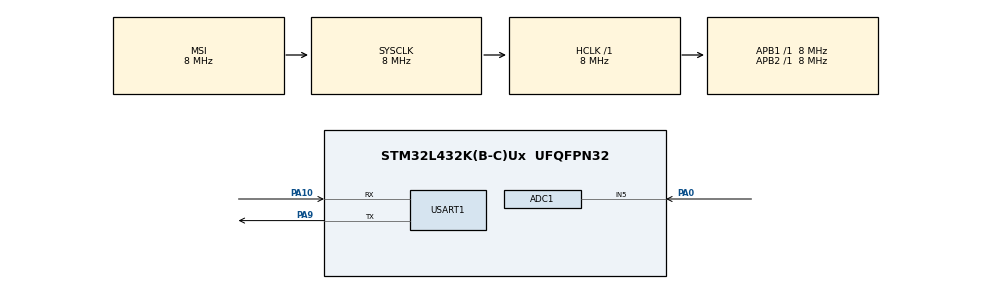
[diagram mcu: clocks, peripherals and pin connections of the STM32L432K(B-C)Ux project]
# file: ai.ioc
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ADC1.Channel-0\#ChannelRegularConversion=ADC_CHANNEL_5
ADC1.ContinuousConvMode=ENABLE
ADC1.NbrOfConversionFlag=1
ADC1.OffsetNumber-0\#ChannelRegularConversion=ADC_OFFSET_NONE
ADC1.Rank-0\#ChannelRegularConversion=1
ADC1.SamplingTime-0\#ChannelRegularConversion=ADC_SAMPLETIME_2CYCLES_5
ADC1.master=1
Mcu.Family=STM32L4
Mcu.Name=STM32L432K(B-C)Ux
Mcu.Package=UFQFPN32
NVIC.PriorityGroup=NVIC_PRIORITYGROUP_4
PA0.Signal=ADCx_IN5
PA10.Mode=Asynchronous
PA10.Signal=USART1_RX
PA9.Mode=Asynchronous
PA9.Signal=USART1_TX
ProjectManager.HeapSize=0x2000
ProjectManager.StackSize=0x4000
ProjectManager.TargetToolchain=MDK-ARM V5.27
RCC.ADCFreq_Value=32000000
RCC.AHBFreq_Value=8000000
RCC.APB1Freq_Value=8000000
RCC.APB1TimFreq_Value=8000000
RCC.APB2Freq_Value=8000000
RCC.APB2TimFreq_Value=8000000
RCC.CortexFreq_Value=8000000
RCC.HCLKFreq_Value=8000000
RCC.HSE_VALUE=8000000
RCC.HSI48_VALUE=48000000
RCC.HSI_VALUE=16000000
RCC.LSE_VALUE=32768
RCC.MSIClockRange=RCC_MSIRANGE_7
RCC.MSI_VALUE=8000000
RCC.SYSCLKFreq_VALUE=8000000
RCC.USBFreq_Value=32000000
RCC.VCOOutputFreq_Value=64000000
SH.ADCx_IN5.0=ADC1_IN5,IN5-Single-Ended
STMicroelectronics.X-CUBE-AI.5.0.0.ActivationBufferSizeList=400
STMicroelectronics.X-CUBE-AI.5.0.0.ApplicationCcArtificialOoIntelligenceJjApplication=ApplicationTemplate
STMicroelectronics.X-CUBE-AI.5.0.0.HeapSize=0x2000
STMicroelectronics.X-CUBE-AI.5.0.0.InternalRamActivationBufferMaxSize=AI_ECG_NETWORK_DATA_ACTIVATIONS_SIZE
STMicroelectronics.X-CUBE-AI.5.0.0.LatestDirectoryUsed-d3a59a0a51c23c8c7a7c3687464f654e9c9f9513bd5a042f653194bf225a79ad=C\:\\Users\\shalan\\Desktop\\Embedded\\Proj2
STMicroelectronics.X-CUBE-AI.5.0.0.MaximumNumberOfInputLayer=1
STMicroelectronics.X-CUBE-AI.5.0.0.MaximumNumberOfOutputLayer=1
STMicroelectronics.X-CUBE-AI.5.0.0.MaximumSizeOfInputLayer=748
STMicroelectronics.X-CUBE-AI.5.0.0.MaximumSizeOfOutputLayer=20
STMicroelectronics.X-CUBE-AI.5.0.0.ModelActualCompression-d3a59a0a51c23c8c7a7c3687464f654e9c9f9513bd5a042f653194bf225a79ad=0.0
STMicroelectronics.X-CUBE-AI.5.0.0.ModelCompression-d3a59a0a51c23c8c7a7c3687464f654e9c9f9513bd5a042f653194bf225a79ad=4
STMicroelectronics.X-CUBE-AI.5.0.0.ModelFlashOccupation-d3a59a0a51c23c8c7a7c3687464f654e9c9f9513bd5a042f653194bf225a79ad=15320
STMicroelectronics.X-CUBE-AI.5.0.0.ModelHashList=d3a59a0a51c23c8c7a7c3687464f654e9c9f9513bd5a042f653194bf225a79ad
STMicroelectronics.X-CUBE-AI.5.0.0.ModelKind-d3a59a0a51c23c8c7a7c3687464f654e9c9f9513bd5a042f653194bf225a79ad=KERAS
STMicroelectronics.X-CUBE-AI.5.0.0.ModelMacc-d3a59a0a51c23c8c7a7c3687464f654e9c9f9513bd5a042f653194bf225a79ad=12275
STMicroelectronics.X-CUBE-AI.5.0.0.ModelName-d3a59a0a51c23c8c7a7c3687464f654e9c9f9513bd5a042f653194bf225a79ad=ecg_network
STMicroelectronics.X-CUBE-AI.5.0.0.ModelNameList=ecg_network
STMicroelectronics.X-CUBE-AI.5.0.0.ModelRamOccupation-d3a59a0a51c23c8c7a7c3687464f654e9c9f9513bd5a042f653194bf225a79ad=400
STMicroelectronics.X-CUBE-AI.5.0.0.ModelStructureFile-d3a59a0a51c23c8c7a7c3687464f654e9c9f9513bd5a042f653194bf225a79ad=C\:\\Users\\shalan\\Desktop\\Embedded\\Proj2\\my_model.h5
STMicroelectronics.X-CUBE-AI.5.0.0.ModelType-d3a59a0a51c23c8c7a7c3687464f654e9c9f9513bd5a042f653194bf225a79ad=Saved model
STMicroelectronics.X-CUBE-AI.5.0.0.NNModelInformation_AchievedCompression-d3a59a0a51c23c8c7a7c3687464f654e9c9f9513bd5a042f653194bf225a79ad=0.0
STMicroelectronics.X-CUBE-AI.5.0.0.NNModelInformation_CompressionFactor-d3a59a0a51c23c8c7a7c3687464f654e9c9f9513bd5a042f653194bf225a79ad=-0.6861941827120033
STMicroelectronics.X-CUBE-AI.5.0.0.NNModelInformation_EvaluationStatus-d3a59a0a51c23c8c7a7c3687464f654e9c9f9513bd5a042f653194bf225a79ad=X-cross \#1\: acc\=100.0%,rmse\=0.000132,mae\=0.000033;L2r status\: l2r\=2.95907725e-04,status\=PASSED;
STMicroelectronics.X-CUBE-AI.5.0.0.NNModelInformation_HeapSizeNeeded-d3a59a0a51c23c8c7a7c3687464f654e9c9f9513bd5a042f653194bf225a79ad=2048
STMicroelectronics.X-CUBE-AI.5.0.0.NNModelInformation_ModelInSizeByName-d3a59a0a51c23c8c7a7c3687464f654e9c9f9513bd5a042f653194bf225a79ad={input_0\=748}
STMicroelectronics.X-CUBE-AI.5.0.0.NNModelInformation_ModelMacc-d3a59a0a51c23c8c7a7c3687464f654e9c9f9513bd5a042f653194bf225a79ad=12275
STMicroelectronics.X-CUBE-AI.5.0.0.NNModelInformation_ModelName-d3a59a0a51c23c8c7a7c3687464f654e9c9f9513bd5a042f653194bf225a79ad=ecg_network
STMicroelectronics.X-CUBE-AI.5.0.0.NNModelInformation_ModelOutSizeByName-d3a59a0a51c23c8c7a7c3687464f654e9c9f9513bd5a042f653194bf225a79ad={dense_3_nl\=20}
STMicroelectronics.X-CUBE-AI.5.0.0.NNModelInformation_ModelRam-d3a59a0a51c23c8c7a7c3687464f654e9c9f9513bd5a042f653194bf225a79ad=400
STMicroelectronics.X-CUBE-AI.5.0.0.NNModelInformation_ModelRom-d3a59a0a51c23c8c7a7c3687464f654e9c9f9513bd5a042f653194bf225a79ad=15320
STMicroelectronics.X-CUBE-AI.5.0.0.NNModelInformation_ModelSize-d3a59a0a51c23c8c7a7c3687464f654e9c9f9513bd5a042f653194bf225a79ad=48820
STMicroelectronics.X-CUBE-AI.5.0.0.NNModelInformation_NbOfParameters-d3a59a0a51c23c8c7a7c3687464f654e9c9f9513bd5a042f653194bf225a79ad=12205
STMicroelectronics.X-CUBE-AI.5.0.0.StackSize=0x4000
STMicroelectronics.X-CUBE-AI.5.0.0.WorkingBufferStartAddrList=0xFFFFFFFF
STMicroelectronics.X-CUBE-AI.5.0.0.XAaCUBEAaAICcArtificialOoIntelligenceJjCore=true
TIM1.Period=49999
TIM1.Prescaler=7
USART1.VirtualMode-Asynchronous=VM_ASYNC
VP_CRC_VS_CRC.Mode=CRC_Activate
VP_STMicroelectronics.X-CUBE-AI_VS_ArtificialOoIntelligenceJjApplication_5.0.0.Mode=ArtificialOoIntelligenceJjApplication
VP_STMicroelectronics.X-CUBE-AI_VS_ArtificialOoIntelligenceJjXAaCUBEAaAI_5.0.0.Mode=ArtificialOoIntelligenceJjXAaCUBEAaAI
VP_TIM1_VS_ClockSourceINT.Mode=Internal
board=custom

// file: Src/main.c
/* USER CODE BEGIN Header */
/**
  ******************************************************************************
  * @file           : main.c
  * @brief          : Main program body
  ******************************************************************************
  * @attention
  *
  * <h2><center>&copy; Copyright (c) 2020 STMicroelectronics.
  * All rights reserved.</center></h2>
  *
  * This software component is licensed by ST under Ultimate Liberty license
  * SLA0044, the "License"; You may not use this file except in compliance with
  * the License. You may obtain a copy of the License at:
  *                             www.st.com/SLA0044
  *
  ******************************************************************************
  */
/* USER CODE END Header */

#include "main.h"
#include "app_x-cube-ai.h"

ADC_HandleTypeDef hadc1;

CRC_HandleTypeDef hcrc;

TIM_HandleTypeDef htim1;

UART_HandleTypeDef huart1;

/* USER CODE BEGIN PV */
	float prediction;
/* USER CODE END PV */

void SystemClock_Config(void);
static void MX_GPIO_Init(void);
static void MX_ADC1_Init(void);
static void MX_CRC_Init(void);
static void MX_TIM1_Init(void);
static void MX_USART1_UART_Init(void);

int main(void)
{

  /* MCU Configuration--------------------------------------------------------*/

  /* Reset of all peripherals, Initializes the Flash interface and the Systick. */
  HAL_Init();

  /* Configure the system clock */
  SystemClock_Config();

  /* Initialize all configured peripherals */
  MX_GPIO_Init();
  MX_ADC1_Init();
  MX_CRC_Init();
  MX_TIM1_Init();
  MX_USART1_UART_Init();
  MX_X_CUBE_AI_Init();
  /* USER CODE BEGIN 2 */
	uint8_t output[20];
	HAL_ADC_Start(&hadc1);
	float ADCValue[187];
	float max, min;
	int normal_count;
  /* USER CODE END 2 */

  /* Infinite loop */
  while (1)
  {

    /* USER CODE BEGIN 3 */
		normal_count = 0;
		for(int k = 0; k < 5; k++){
			for(int i = 0; i < 187; ++i){
					HAL_TIM_Base_Start(&htim1);
					__HAL_TIM_SET_COUNTER(&htim1, 0);
					if(HAL_ADC_PollForConversion(&hadc1, 1000000) == HAL_OK){
						ADCValue[i] = HAL_ADC_GetValue(&hadc1);
					}
					while(__HAL_TIM_GET_COUNTER(&htim1) < 8000);
			}

			/*for(int i = 0; i < 1250; i++){
				sprintf(output, "%d\r\n", ADCValue[i]);
				HAL_UART_Transmit(&huart1, output, sizeof(output), 100);
			}
			HAL_UART_Transmit(&huart1, "---\r\n", 5, 100);*/

			max = ADCValue[0], min = ADCValue[0];
			for (int i=0; i<187; ++i){
				if (ADCValue[i] > max){
					max = ADCValue[i];
				}
				else if(ADCValue[i] < min)
					min = ADCValue[i];
			}

			for(int i = 0; i < 187; ++i)
				ADCValue[i] = (ADCValue[i] - min)/(max - min);

			prediction = MX_X_CUBE_AI_Process(ADCValue);

			if(prediction > 0.5 && min > 1000)
				normal_count++;

		}
		if(normal_count >= 3)
			HAL_UART_Transmit(&huart1, "Normal\r\n", 8, 100);
		else
			HAL_UART_Transmit(&huart1, "Abnormal\r\n", 10, 100);

  }
  /* USER CODE END 3 */
}

void SystemClock_Config(void)
{
  RCC_OscInitTypeDef RCC_OscInitStruct = {0};
  RCC_ClkInitTypeDef RCC_ClkInitStruct = {0};
  RCC_PeriphCLKInitTypeDef PeriphClkInit = {0};

  /** Initializes the CPU, AHB and APB busses clocks
  */
  RCC_OscInitStruct.OscillatorType = RCC_OSCILLATORTYPE_MSI;
  RCC_OscInitStruct.MSIState = RCC_MSI_ON;
  RCC_OscInitStruct.MSICalibrationValue = 0;
  RCC_OscInitStruct.MSIClockRange = RCC_MSIRANGE_7;
  RCC_OscInitStruct.PLL.PLLState = RCC_PLL_NONE;
  if (HAL_RCC_OscConfig(&RCC_OscInitStruct) != HAL_OK)
  {
    Error_Handler();
  }
  /** Initializes the CPU, AHB and APB busses clocks
  */
  RCC_ClkInitStruct.ClockType = RCC_CLOCKTYPE_HCLK|RCC_CLOCKTYPE_SYSCLK
                              |RCC_CLOCKTYPE_PCLK1|RCC_CLOCKTYPE_PCLK2;
  RCC_ClkInitStruct.SYSCLKSource = RCC_SYSCLKSOURCE_MSI;
  RCC_ClkInitStruct.AHBCLKDivider = RCC_SYSCLK_DIV1;
  RCC_ClkInitStruct.APB1CLKDivider = RCC_HCLK_DIV1;
  RCC_ClkInitStruct.APB2CLKDivider = RCC_HCLK_DIV1;

  if (HAL_RCC_ClockConfig(&RCC_ClkInitStruct, FLASH_LATENCY_0) != HAL_OK)
  {
    Error_Handler();
  }
  PeriphClkInit.PeriphClockSelection = RCC_PERIPHCLK_USART1|RCC_PERIPHCLK_ADC;
  PeriphClkInit.Usart1ClockSelection = RCC_USART1CLKSOURCE_PCLK2;
  PeriphClkInit.AdcClockSelection = RCC_ADCCLKSOURCE_PLLSAI1;
  PeriphClkInit.PLLSAI1.PLLSAI1Source = RCC_PLLSOURCE_MSI;
  PeriphClkInit.PLLSAI1.PLLSAI1M = 1;
  PeriphClkInit.PLLSAI1.PLLSAI1N = 8;
  PeriphClkInit.PLLSAI1.PLLSAI1P = RCC_PLLP_DIV7;
  PeriphClkInit.PLLSAI1.PLLSAI1Q = RCC_PLLQ_DIV2;
  PeriphClkInit.PLLSAI1.PLLSAI1R = RCC_PLLR_DIV2;
  PeriphClkInit.PLLSAI1.PLLSAI1ClockOut = RCC_PLLSAI1_ADC1CLK;
  if (HAL_RCCEx_PeriphCLKConfig(&PeriphClkInit) != HAL_OK)
  {
    Error_Handler();
  }
  /** Configure the main internal regulator output voltage
  */
  if (HAL_PWREx_ControlVoltageScaling(PWR_REGULATOR_VOLTAGE_SCALE1) != HAL_OK)
  {
    Error_Handler();
  }
}

static void MX_ADC1_Init(void)
{

  ADC_ChannelConfTypeDef sConfig = {0};

  /** Common config
  */
  hadc1.Instance = ADC1;
  hadc1.Init.ClockPrescaler = ADC_CLOCK_ASYNC_DIV1;
  hadc1.Init.Resolution = ADC_RESOLUTION_12B;
  hadc1.Init.DataAlign = ADC_DATAALIGN_RIGHT;
  hadc1.Init.ScanConvMode = ADC_SCAN_DISABLE;
  hadc1.Init.EOCSelection = ADC_EOC_SINGLE_CONV;
  hadc1.Init.LowPowerAutoWait = DISABLE;
  hadc1.Init.ContinuousConvMode = ENABLE;
  hadc1.Init.NbrOfConversion = 1;
  hadc1.Init.DiscontinuousConvMode = DISABLE;
  hadc1.Init.NbrOfDiscConversion = 1;
  hadc1.Init.ExternalTrigConv = ADC_SOFTWARE_START;
  hadc1.Init.ExternalTrigConvEdge = ADC_EXTERNALTRIGCONVEDGE_NONE;
  hadc1.Init.DMAContinuousRequests = DISABLE;
  hadc1.Init.Overrun = ADC_OVR_DATA_OVERWRITTEN;
  hadc1.Init.OversamplingMode = DISABLE;
  if (HAL_ADC_Init(&hadc1) != HAL_OK)
  {
    Error_Handler();
  }
  /** Configure Regular Channel
  */
  sConfig.Channel = ADC_CHANNEL_5;
  sConfig.Rank = ADC_REGULAR_RANK_1;
  sConfig.SamplingTime = ADC_SAMPLETIME_2CYCLES_5;
  sConfig.SingleDiff = ADC_SINGLE_ENDED;
  sConfig.OffsetNumber = ADC_OFFSET_NONE;
  sConfig.Offset = 0;
  if (HAL_ADC_ConfigChannel(&hadc1, &sConfig) != HAL_OK)
  {
    Error_Handler();
  }

}

static void MX_CRC_Init(void)
{

  hcrc.Instance = CRC;
  hcrc.Init.DefaultPolynomialUse = DEFAULT_POLYNOMIAL_ENABLE;
  hcrc.Init.DefaultInitValueUse = DEFAULT_INIT_VALUE_ENABLE;
  hcrc.Init.InputDataInversionMode = CRC_INPUTDATA_INVERSION_NONE;
  hcrc.Init.OutputDataInversionMode = CRC_OUTPUTDATA_INVERSION_DISABLE;
  hcrc.InputDataFormat = CRC_INPUTDATA_FORMAT_BYTES;
  if (HAL_CRC_Init(&hcrc) != HAL_OK)
  {
    Error_Handler();
  }

}

static void MX_TIM1_Init(void)
{

  TIM_ClockConfigTypeDef sClockSourceConfig = {0};
  TIM_MasterConfigTypeDef sMasterConfig = {0};

  htim1.Instance = TIM1;
  htim1.Init.Prescaler = 7;
  htim1.Init.CounterMode = TIM_COUNTERMODE_UP;
  htim1.Init.Period = 49999;
  htim1.Init.ClockDivision = TIM_CLOCKDIVISION_DIV1;
  htim1.Init.RepetitionCounter = 0;
  htim1.Init.AutoReloadPreload = TIM_AUTORELOAD_PRELOAD_DISABLE;
  if (HAL_TIM_Base_Init(&htim1) != HAL_OK)
  {
    Error_Handler();
  }
  sClockSourceConfig.ClockSource = TIM_CLOCKSOURCE_INTERNAL;
  if (HAL_TIM_ConfigClockSource(&htim1, &sClockSourceConfig) != HAL_OK)
  {
    Error_Handler();
  }
  sMasterConfig.MasterOutputTrigger = TIM_TRGO_RESET;
  sMasterConfig.MasterOutputTrigger2 = TIM_TRGO2_RESET;
  sMasterConfig.MasterSlaveMode = TIM_MASTERSLAVEMODE_DISABLE;
  if (HAL_TIMEx_MasterConfigSynchronization(&htim1, &sMasterConfig) != HAL_OK)
  {
    Error_Handler();
  }

}

static void MX_USART1_UART_Init(void)
{

  huart1.Instance = USART1;
  huart1.Init.BaudRate = 115200;
  huart1.Init.WordLength = UART_WORDLENGTH_8B;
  huart1.Init.StopBits = UART_STOPBITS_1;
  huart1.Init.Parity = UART_PARITY_NONE;
  huart1.Init.Mode = UART_MODE_TX_RX;
  huart1.Init.HwFlowCtl = UART_HWCONTROL_NONE;
  huart1.Init.OverSampling = UART_OVERSAMPLING_16;
  huart1.Init.OneBitSampling = UART_ONE_BIT_SAMPLE_DISABLE;
  huart1.AdvancedInit.AdvFeatureInit = UART_ADVFEATURE_NO_INIT;
  if (HAL_UART_Init(&huart1) != HAL_OK)
  {
    Error_Handler();
  }

}

static void MX_GPIO_Init(void)
{

	GPIO_InitTypeDef GPIO_InitStruct = {0};

  /* GPIO Ports Clock Enable */
  __HAL_RCC_GPIOA_CLK_ENABLE();

	/*Configure GPIO pins : PA5 PA6 */
  GPIO_InitStruct.Pin = GPIO_PIN_5|GPIO_PIN_6;
  GPIO_InitStruct.Mode = GPIO_MODE_INPUT;
  GPIO_InitStruct.Pull = GPIO_NOPULL;
  HAL_GPIO_Init(GPIOA, &GPIO_InitStruct);

}

void Error_Handler(void)
{
}

/************************ (C) COPYRIGHT STMicroelectronics *****END OF FILE****/
